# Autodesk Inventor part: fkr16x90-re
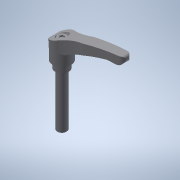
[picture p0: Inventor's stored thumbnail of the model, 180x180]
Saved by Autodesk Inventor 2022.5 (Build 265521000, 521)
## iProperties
Created: 2017-09
Part Number: fkr16x90-re
Material: 一般
Document SubType Name: Modeling
Designer: imaocorp
Density: 1 g/cm^3
Appearance: 既定
Author: imaocorp
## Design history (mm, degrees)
node "fkr16x90-re.x_t1"
node "fkr16x90-re"
node "Base1"
